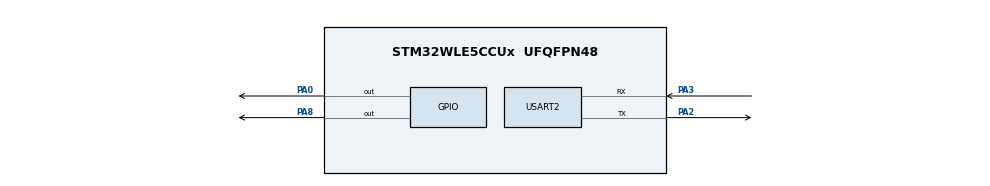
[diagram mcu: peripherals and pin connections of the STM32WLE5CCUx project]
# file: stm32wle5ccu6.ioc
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Mcu.Family=STM32WL
Mcu.Name=STM32WLE5CCUx
Mcu.Package=UFQFPN48
NVIC.PriorityGroup=NVIC_PRIORITYGROUP_4
PA0.Signal=GPIO_Output
PA2.Mode=Asynchronous
PA2.Signal=USART2_TX
PA3.Mode=Asynchronous
PA3.Signal=USART2_RX
PA8.Signal=GPIO_Output
ProjectManager.HeapSize=0x200
ProjectManager.StackSize=0x400
ProjectManager.TargetToolchain=STM32CubeIDE
RCC.HSE_VALUE=8000000
RCC.HSI_VALUE=16000000
RCC.LSE_VALUE=32768
RCC.VCOOutputFreq_Value=32000000
USART2.VirtualMode-Asynchronous=VM_ASYNC
VP_TIM2_VS_ClockSourceINT.Mode=Internal
board=custom

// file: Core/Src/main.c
/* USER CODE BEGIN Header */
/* USER CODE END Header */
#include "main.h"

/* USER CODE BEGIN Includes */
#include "string.h"
/* USER CODE END Includes */

/* USER CODE BEGIN PV */
#define DS18B20_PORT GPIOA
#define DS18B20_PIN GPIO_PIN_0
/* USER CODE END Includes */

/* Private typedef -----------------------------------------------------------*/
/* USER CODE BEGIN PTD */
/* USER CODE END PTD */

/* Private define ------------------------------------------------------------*/
/* USER CODE BEGIN PD */
/* USER CODE END PD */

/* Private macro -------------------------------------------------------------*/
/* USER CODE BEGIN PM */
/* USER CODE END PM */

/* Private variables ---------------------------------------------------------*/
TIM_HandleTypeDef htim2;

UART_HandleTypeDef huart2;

/* USER CODE BEGIN PV */
/* USER CODE END PV */

void SystemClock_Config(void);
static void MX_GPIO_Init(void);
static void MX_TIM2_Init(void);
static void MX_USART2_UART_Init(void);

/* USER CODE BEGIN 0 */

int _write(int file, char *ptr, int len)
{
    HAL_UART_Transmit(&huart2, (uint8_t*)ptr, len, HAL_MAX_DELAY);
    return len;
}

void delay_us(uint32_t us)
{
    __HAL_TIM_SET_COUNTER(&htim2, 0);
    while (__HAL_TIM_GET_COUNTER(&htim2) < us);
}

//void delay_us(uint16_t us)
//{
//    uint32_t start = DWT->CYCCNT;
//    uint32_t ticks = us * (HAL_RCC_GetHCLKFreq() / 1000000);
//    while ((DWT->CYCCNT - start) < ticks);
//}

uint8_t DS18B20_Start(void)
{
    uint8_t response = 0;
    GPIO_InitTypeDef GPIO_InitStruct = {0};

    // Set pin as output
    GPIO_InitStruct.Pin = DS18B20_PIN;
    GPIO_InitStruct.Mode = GPIO_MODE_OUTPUT_PP;
    GPIO_InitStruct.Speed = GPIO_SPEED_FREQ_LOW;
    HAL_GPIO_Init(DS18B20_PORT, &GPIO_InitStruct);

    HAL_GPIO_WritePin(DS18B20_PORT, DS18B20_PIN, GPIO_PIN_RESET);
    delay_us(480);

    // Set pin as input
    GPIO_InitStruct.Mode = GPIO_MODE_INPUT;
    HAL_GPIO_Init(DS18B20_PORT, &GPIO_InitStruct);

    delay_us(80);
    if (!HAL_GPIO_ReadPin(DS18B20_PORT, DS18B20_PIN)) response = 1;
    else response = 0;
    delay_us(400);
    return response;
}

void DS18B20_Write(uint8_t data)
{
    GPIO_InitTypeDef GPIO_InitStruct = {0};

    for (int i = 0; i < 8; i++)
    {
        // Set as output
        GPIO_InitStruct.Pin = DS18B20_PIN;
        GPIO_InitStruct.Mode = GPIO_MODE_OUTPUT_PP;
        HAL_GPIO_Init(DS18B20_PORT, &GPIO_InitStruct);

        HAL_GPIO_WritePin(DS18B20_PORT, DS18B20_PIN, GPIO_PIN_RESET);
        delay_us(1);

        if (data & (1 << i))
        {
            HAL_GPIO_WritePin(DS18B20_PORT, DS18B20_PIN, GPIO_PIN_SET);
            delay_us(60);
        }
        else
        {
            delay_us(60);
            HAL_GPIO_WritePin(DS18B20_PORT, DS18B20_PIN, GPIO_PIN_SET);
        }
    }
}

uint8_t DS18B20_Read(void)
{
    uint8_t value = 0;
    GPIO_InitTypeDef GPIO_InitStruct = {0};

    for (int i = 0; i < 8; i++)
    {
        // Set as output
        GPIO_InitStruct.Pin = DS18B20_PIN;
        GPIO_InitStruct.Mode = GPIO_MODE_OUTPUT_PP;
        HAL_GPIO_Init(DS18B20_PORT, &GPIO_InitStruct);

        HAL_GPIO_WritePin(DS18B20_PORT, DS18B20_PIN, GPIO_PIN_RESET);
        delay_us(2);

        // Set as input
        GPIO_InitStruct.Mode = GPIO_MODE_INPUT;
        HAL_GPIO_Init(DS18B20_PORT, &GPIO_InitStruct);

        if (HAL_GPIO_ReadPin(DS18B20_PORT, DS18B20_PIN))
            value |= (1 << i);

        delay_us(60);
    }
    return value;
}

float DS18B20_GetTemp(void)
{
    uint8_t temp_l, temp_h;
    int16_t temp;
    float temperature = 0;

    DS18B20_Start();
    DS18B20_Write(0xCC);  // Skip ROM
    DS18B20_Write(0x44);  // Convert T
    HAL_Delay(750);

    DS18B20_Start();
    DS18B20_Write(0xCC);  // Skip ROM
    DS18B20_Write(0xBE);  // Read Scratchpad

    temp_l = DS18B20_Read();
    temp_h = DS18B20_Read();

    temp = (temp_h << 8) | temp_l;
    temperature = (float)temp / 16.0;

    return temperature;
}
/* USER CODE END 0 */

int main(void)
{

  /* MCU Configuration--------------------------------------------------------*/

  /* Reset of all peripherals, Initializes the Flash interface and the Systick. */
  HAL_Init();

  /* Configure the system clock */
  SystemClock_Config();

  /* Initialize all configured peripherals */
  MX_GPIO_Init();
  MX_TIM2_Init();
  MX_USART2_UART_Init();

  /* Infinite loop */
  /* USER CODE BEGIN WHILE */
  // Enable DWT for microsecond delay
  CoreDebug->DEMCR |= CoreDebug_DEMCR_TRCENA_Msk;
  DWT->CTRL |= DWT_CTRL_CYCCNTENA_Msk;

  char msg[50];
  sprintf(msg, "Temperature: °C\r\n");
    /* USER CODE END WHILE */
  while (1)
  {
      float temp = DS18B20_GetTemp();
      sprintf(msg, "Temperature: %.2f °C\r\n", temp);
      HAL_UART_Transmit(&huart2, (uint8_t*)msg, strlen(msg), HAL_MAX_DELAY);
      HAL_Delay(1000);
  }
}

void SystemClock_Config(void)
{
  RCC_OscInitTypeDef RCC_OscInitStruct = {0};
  RCC_ClkInitTypeDef RCC_ClkInitStruct = {0};

  /** Configure main internal regulator output voltage **/
  HAL_PWREx_ControlVoltageScaling(PWR_REGULATOR_VOLTAGE_SCALE1);

  /** Initializes the RCC Oscillators: HSI ON + PLL ON (48MHz SYSCLK) **/
  RCC_OscInitStruct.OscillatorType = RCC_OSCILLATORTYPE_HSI;
  RCC_OscInitStruct.HSIState = RCC_HSI_ON;
  RCC_OscInitStruct.HSICalibrationValue = RCC_HSICALIBRATION_DEFAULT;
  RCC_OscInitStruct.PLL.PLLState = RCC_PLL_ON;
  RCC_OscInitStruct.PLL.PLLSource = RCC_PLLSOURCE_HSI;
  RCC_OscInitStruct.PLL.PLLM = RCC_PLLM_DIV1;
  RCC_OscInitStruct.PLL.PLLN = 6;        // 8 MHz * 6 = 48 MHz
  RCC_OscInitStruct.PLL.PLLP = RCC_PLLP_DIV2;
  RCC_OscInitStruct.PLL.PLLQ = RCC_PLLQ_DIV2;
  RCC_OscInitStruct.PLL.PLLR = RCC_PLLR_DIV2;
  if (HAL_RCC_OscConfig(&RCC_OscInitStruct) != HAL_OK)
  {
    Error_Handler();
  }

  /** Initializes CPU, AHB, and APB buses clocks **/
  RCC_ClkInitStruct.ClockType = RCC_CLOCKTYPE_SYSCLK | RCC_CLOCKTYPE_HCLK3 |
                                RCC_CLOCKTYPE_HCLK | RCC_CLOCKTYPE_PCLK1 | RCC_CLOCKTYPE_PCLK2;
  RCC_ClkInitStruct.SYSCLKSource = RCC_SYSCLKSOURCE_PLLCLK;
  RCC_ClkInitStruct.AHBCLKDivider = RCC_SYSCLK_DIV1;
  RCC_ClkInitStruct.AHBCLK3Divider = RCC_SYSCLK_DIV1;
  RCC_ClkInitStruct.APB1CLKDivider = RCC_HCLK_DIV1;
  RCC_ClkInitStruct.APB2CLKDivider = RCC_HCLK_DIV1;

  if (HAL_RCC_ClockConfig(&RCC_ClkInitStruct, FLASH_LATENCY_2) != HAL_OK)
  {
    Error_Handler();
  }
}

static void MX_TIM2_Init(void)
{
  TIM_ClockConfigTypeDef sClockSourceConfig = {0};
  TIM_MasterConfigTypeDef sMasterConfig = {0};

  htim2.Instance = TIM2;
  htim2.Init.Prescaler = 47;                   // 48 MHz / (47+1) = 1 MHz → 1 tick = 1 µs
  htim2.Init.CounterMode = TIM_COUNTERMODE_UP;
  htim2.Init.Period = 0xFFFFFFFF;              // Max 32-bit counter
  htim2.Init.ClockDivision = TIM_CLOCKDIVISION_DIV1;
  htim2.Init.AutoReloadPreload = TIM_AUTORELOAD_PRELOAD_DISABLE;
  if (HAL_TIM_Base_Init(&htim2) != HAL_OK)
  {
    Error_Handler();
  }

  sClockSourceConfig.ClockSource = TIM_CLOCKSOURCE_INTERNAL;
  if (HAL_TIM_ConfigClockSource(&htim2, &sClockSourceConfig) != HAL_OK)
  {
    Error_Handler();
  }

  sMasterConfig.MasterOutputTrigger = TIM_TRGO_RESET;
  sMasterConfig.MasterSlaveMode = TIM_MASTERSLAVEMODE_DISABLE;
  if (HAL_TIMEx_MasterConfigSynchronization(&htim2, &sMasterConfig) != HAL_OK)
  {
    Error_Handler();
  }

  HAL_TIM_Base_Start(&htim2);   // Start the timer
}

//void SystemClock_Config(void)
//{
//  RCC_OscInitTypeDef RCC_OscInitStruct = {0};
//  RCC_ClkInitTypeDef RCC_ClkInitStruct = {0};
//
//  /** Configure the main internal regulator output voltage
//  */
//  __HAL_PWR_VOLTAGESCALING_CONFIG(PWR_REGULATOR_VOLTAGE_SCALE2);
//
//  /** Initializes the CPU, AHB and APB buses clocks
//  */
//  RCC_OscInitStruct.OscillatorType = RCC_OSCILLATORTYPE_MSI;
//  RCC_OscInitStruct.MSIState = RCC_MSI_ON;
//  RCC_OscInitStruct.MSICalibrationValue = RCC_MSICALIBRATION_DEFAULT;
//  RCC_OscInitStruct.MSIClockRange = RCC_MSIRANGE_6;
//  RCC_OscInitStruct.PLL.PLLState = RCC_PLL_NONE;
//  if (HAL_RCC_OscConfig(&RCC_OscInitStruct) != HAL_OK)
//  {
//    Error_Handler();
//  }
//
//  /** Configure the SYSCLKSource, HCLK, PCLK1 and PCLK2 clocks dividers
//  */
//  RCC_ClkInitStruct.ClockType = RCC_CLOCKTYPE_HCLK3|RCC_CLOCKTYPE_HCLK
//                              |RCC_CLOCKTYPE_SYSCLK|RCC_CLOCKTYPE_PCLK1
//                              |RCC_CLOCKTYPE_PCLK2;
//  RCC_ClkInitStruct.SYSCLKSource = RCC_SYSCLKSOURCE_MSI;
//  RCC_ClkInitStruct.AHBCLKDivider = RCC_SYSCLK_DIV1;
//  RCC_ClkInitStruct.APB1CLKDivider = RCC_HCLK_DIV1;
//  RCC_ClkInitStruct.APB2CLKDivider = RCC_HCLK_DIV1;
//  RCC_ClkInitStruct.AHBCLK3Divider = RCC_SYSCLK_DIV1;
//
//  if (HAL_RCC_ClockConfig(&RCC_ClkInitStruct, FLASH_LATENCY_0) != HAL_OK)
//  {
//    Error_Handler();
//  }
//}
//
///**
//  * @brief TIM2 Initialization Function
//  * @param None
//  * @retval None
//  */
//static void MX_TIM2_Init(void)
//{
//
//  /* USER CODE BEGIN TIM2_Init 0 */
//  /* USER CODE END TIM2_Init 0 */
//
//  TIM_ClockConfigTypeDef sClockSourceConfig = {0};
//  TIM_MasterConfigTypeDef sMasterConfig = {0};
//
//  /* USER CODE BEGIN TIM2_Init 1 */
//  /* USER CODE END TIM2_Init 1 */
//  htim2.Instance = TIM2;
//  htim2.Init.Prescaler = 0;
//  htim2.Init.CounterMode = TIM_COUNTERMODE_UP;
//  htim2.Init.Period = 4294967295;
//  htim2.Init.ClockDivision = TIM_CLOCKDIVISION_DIV1;
//  htim2.Init.AutoReloadPreload = TIM_AUTORELOAD_PRELOAD_DISABLE;
//  if (HAL_TIM_Base_Init(&htim2) != HAL_OK)
//  {
//    Error_Handler();
//  }
//  sClockSourceConfig.ClockSource = TIM_CLOCKSOURCE_INTERNAL;
//  if (HAL_TIM_ConfigClockSource(&htim2, &sClockSourceConfig) != HAL_OK)
//  {
//    Error_Handler();
//  }
//  sMasterConfig.MasterOutputTrigger = TIM_TRGO_RESET;
//  sMasterConfig.MasterSlaveMode = TIM_MASTERSLAVEMODE_DISABLE;
//  if (HAL_TIMEx_MasterConfigSynchronization(&htim2, &sMasterConfig) != HAL_OK)
//  {
//    Error_Handler();
//  }
//  /* USER CODE BEGIN TIM2_Init 2 */
//  /* USER CODE END TIM2_Init 2 */
//
//}

static void MX_USART2_UART_Init(void)
{

  huart2.Instance = USART2;
  huart2.Init.BaudRate = 115200;
  huart2.Init.WordLength = UART_WORDLENGTH_8B;
  huart2.Init.StopBits = UART_STOPBITS_1;
  huart2.Init.Parity = UART_PARITY_NONE;
  huart2.Init.Mode = UART_MODE_TX_RX;
  huart2.Init.HwFlowCtl = UART_HWCONTROL_NONE;
  huart2.Init.OverSampling = UART_OVERSAMPLING_16;
  huart2.Init.OneBitSampling = UART_ONE_BIT_SAMPLE_DISABLE;
  huart2.Init.ClockPrescaler = UART_PRESCALER_DIV1;
  huart2.AdvancedInit.AdvFeatureInit = UART_ADVFEATURE_NO_INIT;
  if (HAL_UART_Init(&huart2) != HAL_OK)
  {
    Error_Handler();
  }
  if (HAL_UARTEx_SetTxFifoThreshold(&huart2, UART_TXFIFO_THRESHOLD_1_8) != HAL_OK)
  {
    Error_Handler();
  }
  if (HAL_UARTEx_SetRxFifoThreshold(&huart2, UART_RXFIFO_THRESHOLD_1_8) != HAL_OK)
  {
    Error_Handler();
  }
  if (HAL_UARTEx_DisableFifoMode(&huart2) != HAL_OK)
  {
    Error_Handler();
  }

}

static void MX_GPIO_Init(void)
{
  GPIO_InitTypeDef GPIO_InitStruct = {0};

  /* GPIO Ports Clock Enable */
  __HAL_RCC_GPIOA_CLK_ENABLE();

  /*Configure GPIO pin Output Level */
  HAL_GPIO_WritePin(GPIOA, GPIO_PIN_0|GPIO_PIN_8, GPIO_PIN_RESET);

  /*Configure GPIO pins : PA0 PA8 */
  GPIO_InitStruct.Pin = GPIO_PIN_0|GPIO_PIN_8;
  GPIO_InitStruct.Mode = GPIO_MODE_OUTPUT_PP;
  GPIO_InitStruct.Pull = GPIO_NOPULL;
  GPIO_InitStruct.Speed = GPIO_SPEED_FREQ_LOW;
  HAL_GPIO_Init(GPIOA, &GPIO_InitStruct);

}

void Error_Handler(void)
{
}
